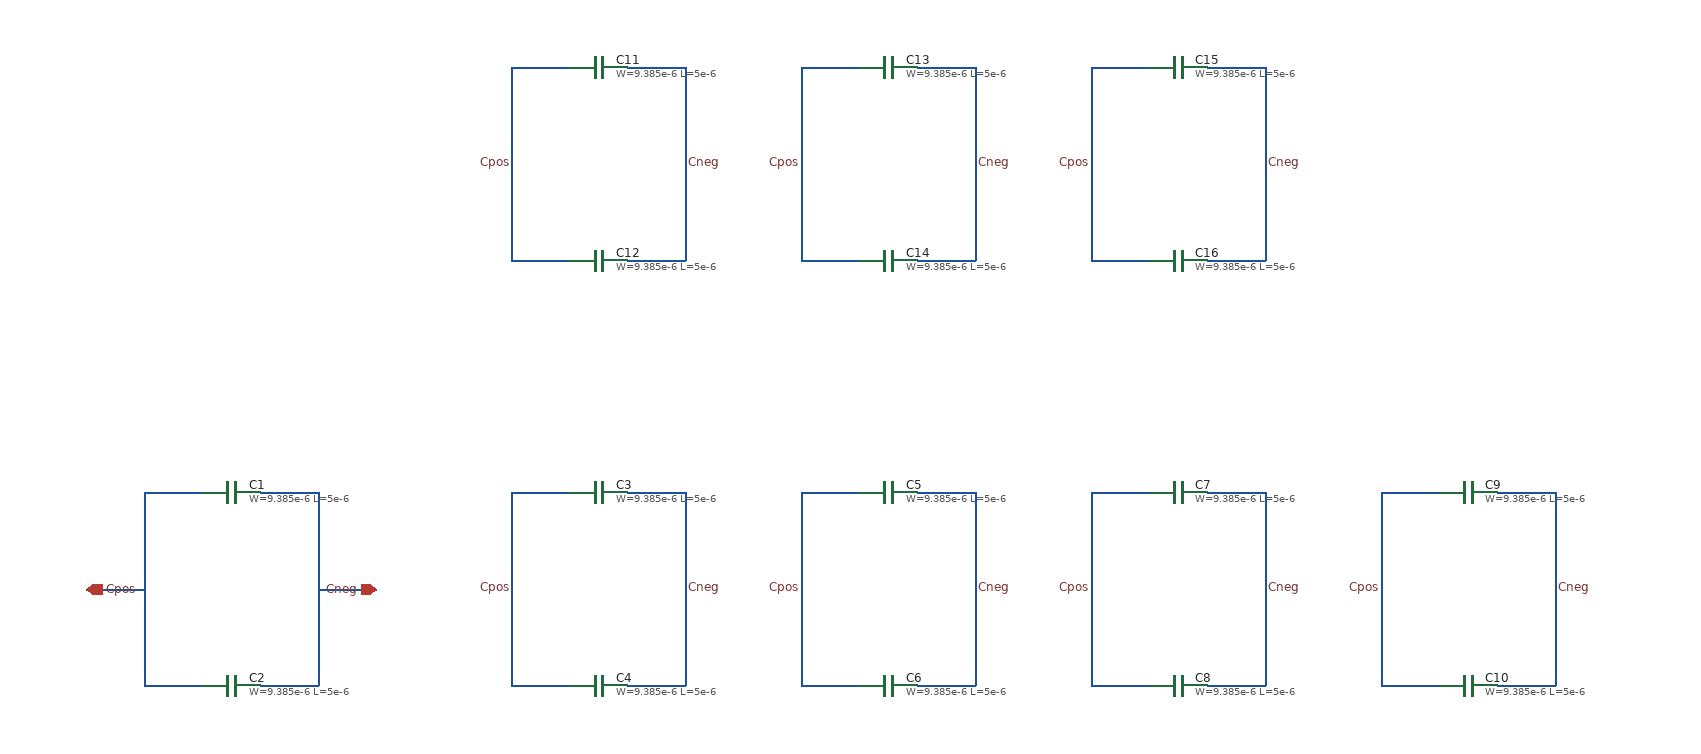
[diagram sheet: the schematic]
v {xschem version=3.4.8RC file_version=1.3}
G {}
K {}
V {}
S {}
F {}
E {}
N 740 -480 800 -480 {lab=Cneg}
N 620 -480 680 -480 {lab=Cpos}
N 620 -280 680 -280 {lab=Cpos}
N 740 -280 800 -280 {lab=Cneg}
N 360 -480 420 -480 {lab=Cneg}
N 240 -480 300 -480 {lab=Cpos}
N 240 -280 300 -280 {lab=Cpos}
N 360 -280 420 -280 {lab=Cneg}
N 420 -480 420 -280 {lab=Cneg}
N 240 -480 240 -280 {lab=Cpos}
N 180 -380 240 -380 {lab=Cpos}
N 420 -380 480 -380 {lab=Cneg}
N 620 -480 620 -280 {lab=Cpos}
N 800 -480 800 -280 {lab=Cneg}
N 1040 -480 1100 -480 {lab=Cneg}
N 920 -480 980 -480 {lab=Cpos}
N 920 -280 980 -280 {lab=Cpos}
N 1040 -280 1100 -280 {lab=Cneg}
N 920 -480 920 -280 {lab=Cpos}
N 1100 -480 1100 -280 {lab=Cneg}
N 1340 -480 1400 -480 {lab=Cneg}
N 1220 -480 1280 -480 {lab=Cpos}
N 1220 -280 1280 -280 {lab=Cpos}
N 1340 -280 1400 -280 {lab=Cneg}
N 1220 -480 1220 -280 {lab=Cpos}
N 1400 -480 1400 -280 {lab=Cneg}
N 1640 -480 1700 -480 {lab=Cneg}
N 1520 -480 1580 -480 {lab=Cpos}
N 1520 -280 1580 -280 {lab=Cpos}
N 1640 -280 1700 -280 {lab=Cneg}
N 1520 -480 1520 -280 {lab=Cpos}
N 1700 -480 1700 -280 {lab=Cneg}
N 740 -920 800 -920 {lab=Cneg}
N 620 -920 680 -920 {lab=Cpos}
N 620 -720 680 -720 {lab=Cpos}
N 740 -720 800 -720 {lab=Cneg}
N 620 -920 620 -720 {lab=Cpos}
N 800 -920 800 -720 {lab=Cneg}
N 1040 -920 1100 -920 {lab=Cneg}
N 920 -920 980 -920 {lab=Cpos}
N 920 -720 980 -720 {lab=Cpos}
N 1040 -720 1100 -720 {lab=Cneg}
N 920 -920 920 -720 {lab=Cpos}
N 1100 -920 1100 -720 {lab=Cneg}
N 1340 -920 1400 -920 {lab=Cneg}
N 1220 -920 1280 -920 {lab=Cpos}
N 1220 -720 1280 -720 {lab=Cpos}
N 1340 -720 1400 -720 {lab=Cneg}
N 1220 -920 1220 -720 {lab=Cpos}
N 1400 -920 1400 -720 {lab=Cneg}
C {iopin.sym} 180 -380 0 1 {name=p3 lab=Cpos}
C {iopin.sym} 480 -380 0 0 {name=p4 lab=Cneg}
C {lab_pin.sym} 620 -380 0 0 {name=p20 lab=Cpos}
C {lab_pin.sym} 800 -380 0 1 {name=p5 lab=Cneg}
C {lab_pin.sym} 920 -380 0 0 {name=p1 lab=Cpos}
C {lab_pin.sym} 1100 -380 0 1 {name=p2 lab=Cneg}
C {lab_pin.sym} 1220 -380 0 0 {name=p6 lab=Cpos}
C {lab_pin.sym} 1400 -380 0 1 {name=p7 lab=Cneg}
C {lab_pin.sym} 1520 -380 0 0 {name=p8 lab=Cpos}
C {lab_pin.sym} 1700 -380 0 1 {name=p9 lab=Cneg}
C {symbols/cap_mim_2f0fF.sym} 330 -480 3 0 {name=C1
W=9.385e-6
L=5e-6
model=cap_mim_2f0fF
spiceprefix=X
m=1}
C {symbols/cap_mim_2f0fF.sym} 330 -280 3 1 {name=C2
W=9.385e-6
L=5e-6
model=cap_mim_2f0fF
spiceprefix=X
m=1}
C {symbols/cap_mim_2f0fF.sym} 710 -480 3 0 {name=C3
W=9.385e-6
L=5e-6
model=cap_mim_2f0fF
spiceprefix=X
m=1}
C {symbols/cap_mim_2f0fF.sym} 710 -280 3 1 {name=C4
W=9.385e-6
L=5e-6
model=cap_mim_2f0fF
spiceprefix=X
m=1}
C {symbols/cap_mim_2f0fF.sym} 1010 -480 3 0 {name=C5
W=9.385e-6
L=5e-6
model=cap_mim_2f0fF
spiceprefix=X
m=1}
C {symbols/cap_mim_2f0fF.sym} 1010 -280 3 1 {name=C6
W=9.385e-6
L=5e-6
model=cap_mim_2f0fF
spiceprefix=X
m=1}
C {symbols/cap_mim_2f0fF.sym} 1310 -480 3 0 {name=C7
W=9.385e-6
L=5e-6
model=cap_mim_2f0fF
spiceprefix=X
m=1}
C {symbols/cap_mim_2f0fF.sym} 1310 -280 3 1 {name=C8
W=9.385e-6
L=5e-6
model=cap_mim_2f0fF
spiceprefix=X
m=1}
C {symbols/cap_mim_2f0fF.sym} 1610 -480 3 0 {name=C9
W=9.385e-6
L=5e-6
model=cap_mim_2f0fF
spiceprefix=X
m=1}
C {symbols/cap_mim_2f0fF.sym} 1610 -280 3 1 {name=C10
W=9.385e-6
L=5e-6
model=cap_mim_2f0fF
spiceprefix=X
m=1}
C {lab_pin.sym} 620 -820 0 0 {name=p10 lab=Cpos}
C {lab_pin.sym} 800 -820 0 1 {name=p11 lab=Cneg}
C {lab_pin.sym} 920 -820 0 0 {name=p12 lab=Cpos}
C {lab_pin.sym} 1100 -820 0 1 {name=p13 lab=Cneg}
C {lab_pin.sym} 1220 -820 0 0 {name=p14 lab=Cpos}
C {lab_pin.sym} 1400 -820 0 1 {name=p15 lab=Cneg}
C {symbols/cap_mim_2f0fF.sym} 710 -920 3 0 {name=C11
W=9.385e-6
L=5e-6
model=cap_mim_2f0fF
spiceprefix=X
m=1}
C {symbols/cap_mim_2f0fF.sym} 710 -720 3 1 {name=C12
W=9.385e-6
L=5e-6
model=cap_mim_2f0fF
spiceprefix=X
m=1}
C {symbols/cap_mim_2f0fF.sym} 1010 -920 3 0 {name=C13
W=9.385e-6
L=5e-6
model=cap_mim_2f0fF
spiceprefix=X
m=1}
C {symbols/cap_mim_2f0fF.sym} 1010 -720 3 1 {name=C14
W=9.385e-6
L=5e-6
model=cap_mim_2f0fF
spiceprefix=X
m=1}
C {symbols/cap_mim_2f0fF.sym} 1310 -920 3 0 {name=C15
W=9.385e-6
L=5e-6
model=cap_mim_2f0fF
spiceprefix=X
m=1}
C {symbols/cap_mim_2f0fF.sym} 1310 -720 3 1 {name=C16
W=9.385e-6
L=5e-6
model=cap_mim_2f0fF
spiceprefix=X
m=1}
C {title.sym} 360 -100 0 0 {name=l1 author="Sayyad Arif"}
